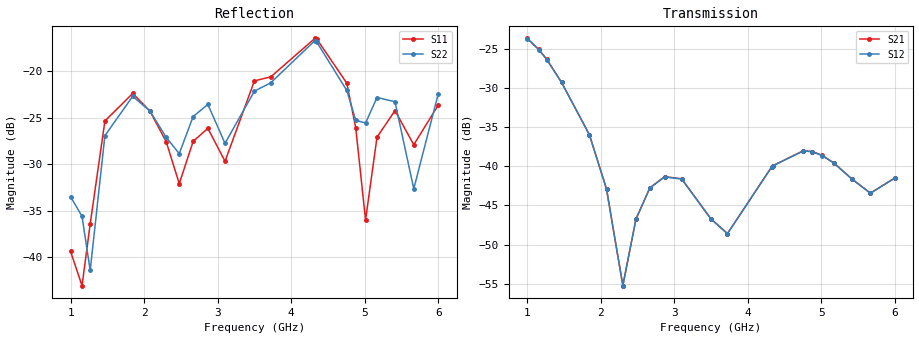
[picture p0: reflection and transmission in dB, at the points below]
!Agilent Technologies,E8364B,MY43040528,A.07.50.67
!Agilent E8364B: A.07.50.67
!Date: Sunday, March 01, 2026 20:49:02
!Correction: S11(Full 2 Port(1,2))
!S21(Full 2 Port(1,2))
!S12(Full 2 Port(1,2))
!S22(Full 2 Port(1,2))
!S2P File: Measurements: S11, S21, S12, S22:
# Hz S  dB  R 50
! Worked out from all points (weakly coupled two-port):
!   451 points, 1 GHz to 6 GHz, reference 50 ohm
!   highest |S21| = -23.64 dB at 1 GHz (marker M1); lowest = -55.3 dB at 2.3 GHz (marker M2)
!   lowest |S11| = -43.1 dB at 1.156 GHz (marker M3), VSWR 1.01, Z = 49.5 + j0.526 ohm
!   |S11| at or under -10 dB: start of sweep to end of sweep
!   |S22| runs from -41.5 to -16.5 dB; largest |S21 - S12| = 0.00018
!   S11 on the Smith chart (normalised r, x): 1 GHz: 1.01, +0.02; 4.322 GHz: 1.24, -0.24; 6 GHz: 0.99, -0.13
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1e9  -39.41 64.5  -23.64 148.7  -23.66 148.7  -33.51 21.0
1.155556e9  -43.10 130.6  -25.05 58.8  -25.07 58.7  -35.61 24.8
1.266667e9  -36.44 -174.9  -26.33 -5.2  -26.36 -5.2  -41.46 68.2
1.466667e9  -25.35 161.9  -29.27 -117.4  -29.28 -117.5  -26.92 84.8
1.844444e9  -22.36 93.8  -35.93 37.9  -35.95 37.8  -22.68 2.4
2.077778e9  -24.26 66.9  -42.87 -85.2  -42.91 -85.2  -24.25 -32.1
2.3e9  -27.57 48.7  -55.25 -132.1  -55.23 -132.3  -27.10 -54.7
2.477778e9  -32.10 65.3  -46.74 -166.5  -46.77 -166.5  -28.86 -46.4
2.666667e9  -27.54 83.1  -42.75 96.5  -42.78 96.5  -24.86 -51.7
2.866667e9  -26.13 57.6  -41.31 -11.1  -41.35 -11.2  -23.55 -88.7
3.1e9  -29.69 67.6  -41.59 -138.0  -41.62 -138.1  -27.75 -109.7
3.5e9  -21.01 50.5  -46.73 23.2  -46.75 23.2  -22.12 -123.2
3.722222e9  -20.58 31.4  -48.58 -52.7  -48.61 -52.6  -21.22 -145.8
4.322222e9  -16.43 -38.7  -40.08 25.0  -40.11 25.1  -16.67 118.1
4.344444e9  -16.46 -42.2  -39.89 12.9  -39.91 12.9  -16.79 113.7
4.755556e9  -21.26 -110.1  -37.99 139.4  -38.03 139.4  -22.04 41.8
4.877778e9  -26.09 -127.5  -38.11 67.3  -38.13 67.3  -25.26 37.2
5.011111e9  -36.02 -91.7  -38.60 -12.2  -38.63 -12.2  -25.56 47.5
5.166667e9  -27.09 -49.6  -39.54 -106.4  -39.57 -106.4  -22.81 35.2
5.411111e9  -24.22 -87.8  -41.57 98.2  -41.60 98.2  -23.26 -15.7
5.666667e9  -27.90 -92.9  -43.42 -81.5  -43.44 -81.5  -32.65 -14.5
6e9  -23.62 -90.6  -41.47 42.0  -41.48 42.0  -22.40 -17.3
